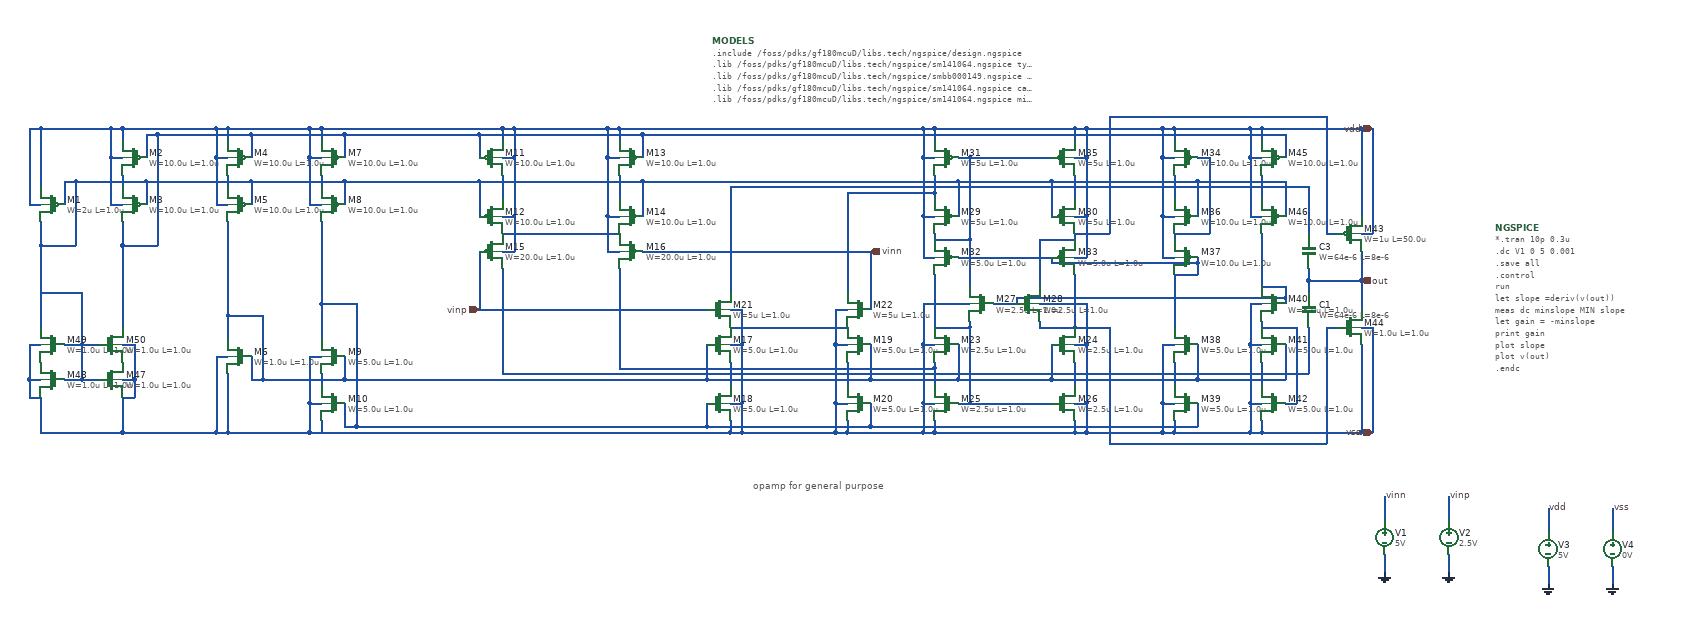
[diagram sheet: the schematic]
v {xschem version=3.4.8RC file_version=1.3}
G {}
K {}
V {}
S {}
F {}
E {}
P 4 1 -50 10 {}
T {opamp for general purpose} 600 240 2 0 0.4 0.4 {}
N 170 -150 190 -150 {
lab=vdd}
N 350 -150 370 -150 {
lab=vdd}
N 170 -360 170 -340 {
lab=vdd}
N 170 -310 190 -310 {
lab=vdd}
N 130 -350 130 -310 {
lab=#net1}
N 890 110 890 160 {
lab=vss}
N 890 110 910 110 {
lab=vss}
N 910 140 910 160 {
lab=vss}
N 910 -360 910 -340 {
lab=vdd}
N 890 -310 910 -310 {
lab=vdd}
N 1150 -360 1150 -340 {
lab=vdd}
N 1150 -310 1170 -310 {
lab=vdd}
N 1170 -310 1170 -210 {
lab=vdd}
N 1150 110 1170 110 {
lab=vss}
N 1150 140 1150 160 {
lab=vss}
N 130 -150 130 -50 {
lab=vinp}
N 740 -50 760 -50 {
lab=vss}
N 560 10 580 10 {
lab=vss}
N 580 110 580 160 {
lab=vss}
N 560 110 580 110 {
lab=vss}
N 560 40 560 80 {
lab=#net2}
N 560 140 560 160 {
lab=vss}
N 520 110 520 150 {
lab=#net3}
N 520 10 520 70 {
lab=#net4}
N 170 -210 190 -210 {
lab=vdd}
N 170 -280 170 -240 {
lab=#net5}
N 130 -270 130 -210 {
lab=#net6}
N 890 -310 890 -210 {
lab=vdd}
N 890 -210 910 -210 {
lab=vdd}
N 910 -250 910 -240 {
lab=#net7}
N 890 10 910 10 {
lab=vss}
N 890 10 890 110 {
lab=vss}
N 910 50 910 80 {
lab=#net8}
N 1150 60 1150 80 {
lab=#net9}
N 1150 10 1170 10 {
lab=vss}
N 410 -150 800 -150 {
lab=vinn}
N 800 -150 800 -50 {
lab=vinn}
N 1150 -210 1170 -210 {
lab=vdd}
N 1150 -260 1150 -240 {
lab=#net10}
N 170 -180 370 -180 {
lab=#net11}
N 130 -50 520 -50 {
lab=vinp}
N 560 -20 760 -20 {
lab=#net12}
N 910 -180 910 -170 {
lab=#net13}
N 890 -140 910 -140 {
lab=vdd}
N 890 -210 890 -140 {
lab=vdd}
N 970 110 1110 110 {
lab=#net14}
N 1170 110 1170 160 {
lab=vss}
N 1010 -60 1050 -60 {
lab=#net15}
N 1150 -140 1170 -140 {
lab=vdd}
N 1170 -210 1170 -140 {
lab=vdd}
N 1150 -180 1150 -170 {
lab=#net16}
N 1090 -60 1170 -60 {
lab=vss}
N 1170 -60 1170 10 {
lab=vss}
N 1640 -100 1640 -50 {
lab=out}
N 1640 -180 1660 -180 {
lab=vdd}
N 1660 -360 1660 -180 {
lab=vdd}
N 1320 -360 1450 -360 {
lab=vdd}
N 1640 -20 1660 -20 {
lab=vss}
N 1660 -20 1660 160 {
lab=vss}
N 1640 10 1640 160 {
lab=vss}
N 1640 -360 1640 -210 {
lab=vdd}
N 1300 -310 1320 -310 {
lab=vdd}
N 1300 -360 1300 -310 {
lab=vdd}
N 1320 -360 1320 -340 {
lab=vdd}
N 1320 -280 1320 -240 {
lab=#net17}
N 1300 -210 1320 -210 {
lab=vdd}
N 1300 -310 1300 -210 {
lab=vdd}
N 1320 -180 1320 -170 {
lab=#net18}
N 1300 -140 1320 -140 {
lab=vdd}
N 1300 -210 1300 -140 {
lab=vdd}
N 1300 10 1320 10 {
lab=vss}
N 1300 110 1300 160 {
lab=vss}
N 1300 110 1320 110 {
lab=vss}
N 1320 40 1320 80 {
lab=#net19}
N 1320 140 1320 160 {
lab=vss}
N 1360 110 1360 150 {
lab=#net3}
N 1360 10 1360 70 {
lab=#net4}
N 1450 -310 1470 -310 {
lab=vdd}
N 1450 -360 1450 -310 {
lab=vdd}
N 1470 -360 1470 -340 {
lab=vdd}
N 1470 -280 1470 -240 {
lab=#net20}
N 1450 -210 1470 -210 {
lab=vdd}
N 1450 -310 1450 -210 {
lab=vdd}
N 1450 10 1470 10 {
lab=vss}
N 1450 110 1450 160 {
lab=vss}
N 1450 110 1470 110 {
lab=vss}
N 1470 40 1470 80 {
lab=#net21}
N 1470 140 1470 160 {
lab=vss}
N 1470 -30 1470 -20 {
lab=#net22}
N 1450 -60 1470 -60 {
lab=vss}
N 1450 -60 1450 10 {
lab=vss}
N 1470 -360 1640 -360 {
lab=vdd}
N 370 -360 370 -340 {
lab=vdd}
N 350 -310 370 -310 {
lab=vdd}
N 410 -350 410 -310 {
lab=#net1}
N 350 -210 370 -210 {
lab=vdd}
N 370 -280 370 -240 {
lab=#net23}
N 410 -270 410 -210 {
lab=#net6}
N 740 10 760 10 {
lab=vss}
N 740 110 760 110 {
lab=vss}
N 760 40 760 80 {
lab=#net24}
N 760 140 760 160 {
lab=vss}
N 800 110 800 150 {
lab=#net3}
N 800 10 800 70 {
lab=#net4}
N 560 -50 580 -50 {
lab=vss}
N 1360 -270 1360 -210 {
lab=#net6}
N 1360 -310 1380 -310 {
lab=#net18}
N 1380 -310 1380 -180 {
lab=#net18}
N 1320 -180 1380 -180 {
lab=#net18}
N 1360 -130 1360 -110 {
lab=#net25}
N 1320 -110 1360 -110 {
lab=#net25}
N 1320 -110 1320 -20 {
lab=#net25}
N 1510 -350 1510 -310 {
lab=#net1}
N 1510 -270 1510 -210 {
lab=#net6}
N 1110 70 1360 70 {
lab=#net4}
N 1510 10 1510 70 {
lab=#net4}
N 1510 110 1530 110 {
lab=#net22}
N 1530 -20 1530 110 {
lab=#net22}
N 1470 -20 1530 -20 {
lab=#net22}
N 1510 -70 1510 -60 {
lab=#net15}
N 1470 -90 1510 -90 {
lab=#net15}
N 1470 -180 1470 -90 {
lab=#net15}
N 970 -310 1110 -310 {
lab=#net13}
N 950 -270 950 -210 {
lab=#net6}
N 1110 -270 1110 -210 {
lab=#net6}
N 950 -140 1110 -140 {
lab=#net25}
N 910 -110 910 -20 {
lab=#net14}
N 970 -30 970 -20 {
lab=#net14}
N 910 -20 970 -20 {
lab=#net14}
N 1090 -30 1090 -20 {
lab=#net26}
N 1090 -20 1150 -20 {
lab=#net26}
N 890 -60 970 -60 {
lab=vss}
N 890 -60 890 10 {
lab=vss}
N 1150 -110 1150 -20 {
lab=#net26}
N 970 -170 970 -90 {
lab=#net13}
N 910 -170 970 -170 {
lab=#net13}
N 1090 -170 1090 -90 {
lab=#net16}
N 1090 -170 1150 -170 {
lab=#net16}
N 1360 -270 1510 -270 {
lab=#net6}
N 800 150 1360 150 {
lab=#net3}
N 1360 70 1510 70 {
lab=#net4}
N 1110 -130 1360 -130 {
lab=#net25}
N 1110 -140 1110 -130 {
lab=#net25}
N 1050 -70 1510 -70 {
lab=#net15}
N 1050 -70 1050 -60 {
lab=#net15}
N 170 -120 170 60 {
lab=#net9}
N 370 -120 370 50 {
lab=#net8}
N 560 -260 560 -80 {
lab=#net10}
N 760 -250 760 -80 {
lab=#net7}
N 950 10 950 70 {
lab=#net4}
N 1110 10 1110 70 {
lab=#net4}
N 970 -20 970 110 {
lab=#net14}
N 970 -310 970 -170 {
lab=#net13}
N 1640 -360 1660 -360 {
lab=vdd}
N 1580 -180 1600 -180 {
lab=#net16}
N 1580 -380 1580 -180 {
lab=#net16}
N 1210 -380 1580 -380 {
lab=#net16}
N 1210 -380 1210 -180 {
lab=#net16}
N 1150 -180 1210 -180 {
lab=#net16}
N 1580 -20 1600 -20 {
lab=#net26}
N 1580 -20 1580 180 {
lab=#net26}
N 1210 180 1580 180 {
lab=#net26}
N 1210 -20 1210 180 {
lab=#net26}
N 1150 -20 1210 -20 {
lab=#net26}
N 1150 60 1550 60 {
lab=#net9}
N 1550 -100 1550 -80 {
lab=out}
N 560 -260 1150 -260 {
lab=#net10}
N 760 -250 910 -250 {
lab=#net7}
N 370 50 910 50 {
lab=#net8}
N 170 60 1150 60 {
lab=#net9}
N 890 -360 910 -360 {
lab=vdd}
N 1150 -360 1170 -360 {
lab=vdd}
N 1640 160 1660 160 {
lab=vss}
N 520 70 800 70 {
lab=#net4}
N 520 150 800 150 {
lab=#net3}
N 130 -350 410 -350 {
lab=#net1}
N 130 -270 410 -270 {
lab=#net6}
N 1110 -270 1360 -270 {
lab=#net6}
N 410 -350 1510 -350 {
lab=#net1}
N 350 -360 370 -360 {
lab=vdd}
N -20 -350 130 -350 {
lab=#net1}
N -20 -270 130 -270 {
lab=#net6}
N -20 70 520 70 {
lab=#net4}
N 0 150 520 150 {
lab=#net3}
N 1550 -100 1640 -100 {
lab=out}
N 1550 -20 1550 60 {
lab=#net9}
N 1150 -260 1550 -260 {
lab=#net10}
N 1550 -260 1550 -180 {
lab=#net10}
N 1550 -120 1550 -100 {
lab=out}
N 350 -310 350 -210 {
lab=vdd}
N 190 -310 190 -210 {
lab=vdd}
N 740 110 740 160 {
lab=vss}
N 580 -50 580 10 {
lab=vss}
N 740 -50 740 10 {
lab=vss}
N 190 -210 190 -150 {
lab=vdd}
N 350 -210 350 -150 {
lab=vdd}
N 190 -360 190 -310 {
lab=vdd}
N 760 160 890 160 {
lab=vss}
N 890 160 910 160 {
lab=vss}
N 890 -360 890 -310 {
lab=vdd}
N 910 -360 1150 -360 {
lab=vdd}
N 1170 -360 1170 -310 {
lab=vdd}
N 1170 10 1170 110 {
lab=vss}
N 910 160 1150 160 {
lab=vss}
N 560 160 580 160 {
lab=vss}
N 580 10 580 110 {
lab=vss}
N 1150 160 1170 160 {
lab=vss}
N 1470 160 1640 160 {
lab=vss}
N 1170 -360 1300 -360 {
lab=vdd}
N 1300 -360 1320 -360 {
lab=vdd}
N 1170 160 1300 160 {
lab=vss}
N 1300 10 1300 110 {
lab=vss}
N 1300 160 1320 160 {
lab=vss}
N 1450 -360 1470 -360 {
lab=vdd}
N 1320 160 1450 160 {
lab=vss}
N 1450 10 1450 110 {
lab=vss}
N 1450 160 1470 160 {
lab=vss}
N 350 -360 350 -310 {
lab=vdd}
N 740 10 740 110 {
lab=vss}
N 740 160 760 160 {
lab=vss}
N 410 -270 950 -270 {
lab=#net6}
N 950 -270 1110 -270 {
lab=#net6}
N 1360 -140 1360 -130 {
lab=#net25}
N 1510 -90 1510 -70 {
lab=#net15}
N 800 70 950 70 {
lab=#net4}
N 950 70 1110 70 {
lab=#net4}
N 950 110 970 110 {
lab=#net14}
N 950 -310 970 -310 {
lab=#net13}
N 1150 40 1150 60 {
lab=#net9}
N 1150 -280 1150 -260 {
lab=#net10}
N 910 -280 910 -250 {
lab=#net7}
N 910 40 910 50 {
lab=#net8}
N 1640 -150 1640 -100 {
lab=out}
N 580 160 740 160 {
lab=vss}
N 170 -360 190 -360 {
lab=vdd}
N 370 -360 890 -360 {
lab=vdd}
N 190 -360 350 -360 {
lab=vdd}
N -160 30 -140 30 {
lab=vss}
N -160 110 -160 160 {
lab=vss}
N -160 110 -140 110 {
lab=vss}
N -140 60 -140 80 {
lab=#net27}
N -140 140 -140 160 {
lab=vss}
N -140 -360 -140 -340 {
lab=vdd}
N -160 -310 -140 -310 {
lab=vdd}
N -160 -230 -140 -230 {
lab=vdd}
N -160 -310 -160 -230 {
lab=vdd}
N -140 -280 -140 -260 {
lab=#net28}
N -100 -270 -100 -230 {
lab=#net6}
N -100 -350 -100 -310 {
lab=#net1}
N -300 -360 -300 -340 {
lab=vdd}
N -320 -310 -300 -310 {
lab=vdd}
N -320 -230 -300 -230 {
lab=vdd}
N -320 -310 -320 -230 {
lab=vdd}
N -300 -280 -300 -260 {
lab=#net29}
N -260 -270 -260 -230 {
lab=#net6}
N -260 -350 -260 -310 {
lab=#net1}
N -320 30 -300 30 {
lab=vss}
N -320 30 -320 160 {
lab=vss}
N -300 60 -300 160 {
lab=vss}
N -260 30 -260 70 {
lab=#net4}
N -260 70 -240 70 {
lab=#net4}
N -300 -40 -240 -40 {
lab=#net4}
N -100 30 -100 70 {
lab=#net4}
N -100 110 -100 150 {
lab=#net3}
N -100 150 -80 150 {
lab=#net3}
N -240 70 -100 70 {
lab=#net4}
N -140 -60 -80 -60 {
lab=#net3}
N -300 -200 -300 -40 {
lab=#net4}
N -140 -200 -140 -60 {
lab=#net3}
N -240 -40 -240 70 {
lab=#net4}
N -80 -60 -80 150 {
lab=#net3}
N -140 -60 -140 0 {
lab=#net3}
N -300 -40 -300 0 {
lab=#net4}
N -100 -350 50 -350 {
lab=#net1}
N -100 -270 50 -270 {
lab=#net6}
N -480 160 -320 160 {
lab=vss}
N -480 -360 -480 -340 {
lab=vdd}
N -500 -310 -480 -310 {
lab=vdd}
N -500 -230 -480 -230 {
lab=vdd}
N -500 -310 -500 -230 {
lab=vdd}
N -480 -280 -480 -260 {
lab=#net30}
N -440 -270 -440 -230 {
lab=#net6}
N -440 -350 -440 -310 {
lab=#net1}
N -480 -160 -420 -160 {
lab=#net1}
N -480 -160 -480 -20 {
lab=#net1}
N -620 -360 -620 -260 {
lab=vdd}
N -640 -230 -620 -230 {
lab=vdd}
N -640 -360 -640 -230 {
lab=vdd}
N -560 -270 -440 -270 {
lab=#net6}
N -580 -270 -580 -230 {
lab=#net6}
N -620 -160 -560 -160 {
lab=#net6}
N -620 -160 -620 -20 {
lab=#net6}
N -620 -200 -620 -160 {
lab=#net6}
N -480 -200 -480 -160 {
lab=#net1}
N -560 -270 -560 -160 {
lab=#net6}
N -420 -350 -420 -160 {
lab=#net1}
N -620 100 -620 160 {
lab=vss}
N -480 100 -480 160 {
lab=vss}
N -550 70 -520 70 {
lab=#net6}
N -640 70 -620 70 {
lab=vss}
N -640 70 -640 100 {
lab=vss}
N -640 100 -620 100 {
lab=vss}
N -480 70 -460 70 {
lab=vss}
N -460 70 -460 100 {
lab=vss}
N -480 100 -460 100 {
lab=vss}
N -550 10 -520 10 {
lab=#net6}
N -550 10 -550 70 {
lab=#net6}
N -640 10 -620 10 {
lab=vss}
N -640 10 -640 70 {
lab=vss}
N -480 10 -460 10 {
lab=vss}
N -460 10 -460 70 {
lab=vss}
N -550 -10 -550 10 {
lab=#net6}
N -300 160 -160 160 {
lab=vss}
N -160 30 -160 110 {
lab=vss}
N -160 160 -140 160 {
lab=vss}
N -160 -360 -140 -360 {
lab=vdd}
N -160 -360 -160 -310 {
lab=vdd}
N -260 -270 -100 -270 {
lab=#net6}
N -260 -350 -100 -350 {
lab=#net1}
N -320 -360 -300 -360 {
lab=vdd}
N -320 -360 -320 -310 {
lab=vdd}
N -440 -270 -260 -270 {
lab=#net6}
N -420 -350 -260 -350 {
lab=#net1}
N -320 160 -300 160 {
lab=vss}
N -500 -360 -480 -360 {
lab=vdd}
N -500 -360 -500 -310 {
lab=vdd}
N -640 -360 -620 -360 {
lab=vdd}
N -580 -270 -560 -270 {
lab=#net6}
N -440 -350 -420 -350 {
lab=#net1}
N -620 160 -480 160 {
lab=vss}
N -580 10 -550 10 {
lab=#net6}
N -580 70 -550 70 {
lab=#net6}
N -300 -360 -160 -360 {
lab=vdd}
N -480 -360 -320 -360 {
lab=vdd}
N -620 -360 -500 -360 {
lab=vdd}
N -620 -80 -550 -80 {lab=#net6}
N -550 -80 -550 -10 {lab=#net6}
N -100 70 40 70 {lab=#net4}
N -80 150 40 150 {lab=#net3}
N -140 -360 170 -360 {lab=vdd}
N -150 160 560 160 {lab=vss}
N 1680 370 1680 400 {lab=GND}
N 1680 270 1680 310 {lab=vinn}
N 1790 370 1790 400 {lab=GND}
N 1790 270 1790 310 {lab=vinp}
N 1960 390 1960 420 {lab=GND}
N 1960 290 1960 330 {lab=vdd}
N 2070 390 2070 420 {lab=GND}
N 2070 290 2070 330 {lab=vss}
C {devices/opin.sym} 1640 -100 0 0 {name=p1 lab=out}
C {devices/iopin.sym} 1660 -360 0 0 {name=p3 lab=vdd}
C {devices/iopin.sym} 1660 160 0 0 {name=p4 lab=vss}
C {devices/ipin.sym} 130 -50 0 0 {name=p2 lab=vinp}
C {devices/ipin.sym} 800 -150 0 1 {name=p5 lab=vinn}
C {symbols/pfet_06v0.sym} 150 -310 0 0 {name=M11
L=1.0u
W=10.0u
nf=1
m=1
ad="'int((nf+1)/2) * W/nf * 0.18u'"
pd="'2*int((nf+1)/2) * (W/nf + 0.18u)'"
as="'int((nf+2)/2) * W/nf * 0.18u'"
ps="'2*int((nf+2)/2) * (W/nf + 0.18u)'"
nrd="'0.18u / W'" nrs="'0.18u / W'"
sa=0 sb=0 sd=0
model=pfet_06v0
spiceprefix=X
}
C {symbols/pfet_06v0.sym} 150 -210 0 0 {name=M12
L=1.0u
W=10.0u
nf=1
m=1
ad="'int((nf+1)/2) * W/nf * 0.18u'"
pd="'2*int((nf+1)/2) * (W/nf + 0.18u)'"
as="'int((nf+2)/2) * W/nf * 0.18u'"
ps="'2*int((nf+2)/2) * (W/nf + 0.18u)'"
nrd="'0.18u / W'" nrs="'0.18u / W'"
sa=0 sb=0 sd=0
model=pfet_06v0
spiceprefix=X
}
C {symbols/pfet_06v0.sym} 390 -310 0 1 {name=M13
L=1.0u
W=10.0u
nf=1
m=1
ad="'int((nf+1)/2) * W/nf * 0.18u'"
pd="'2*int((nf+1)/2) * (W/nf + 0.18u)'"
as="'int((nf+2)/2) * W/nf * 0.18u'"
ps="'2*int((nf+2)/2) * (W/nf + 0.18u)'"
nrd="'0.18u / W'" nrs="'0.18u / W'"
sa=0 sb=0 sd=0
model=pfet_06v0
spiceprefix=X
}
C {symbols/pfet_06v0.sym} 390 -210 0 1 {name=M14
L=1.0u
W=10.0u
nf=1
m=1
ad="'int((nf+1)/2) * W/nf * 0.18u'"
pd="'2*int((nf+1)/2) * (W/nf + 0.18u)'"
as="'int((nf+2)/2) * W/nf * 0.18u'"
ps="'2*int((nf+2)/2) * (W/nf + 0.18u)'"
nrd="'0.18u / W'" nrs="'0.18u / W'"
sa=0 sb=0 sd=0
model=pfet_06v0
spiceprefix=X
}
C {symbols/pfet_06v0.sym} 150 -150 0 0 {name=M15
L=1.0u
W=20.0u
nf=2
m=1
ad="'int((nf+1)/2) * W/nf * 0.18u'"
pd="'2*int((nf+1)/2) * (W/nf + 0.18u)'"
as="'int((nf+2)/2) * W/nf * 0.18u'"
ps="'2*int((nf+2)/2) * (W/nf + 0.18u)'"
nrd="'0.18u / W'" nrs="'0.18u / W'"
sa=0 sb=0 sd=0
model=pfet_06v0
spiceprefix=X
}
C {symbols/pfet_06v0.sym} 390 -150 0 1 {name=M16
L=1.0u
W=20.0u
nf=2
m=1
ad="'int((nf+1)/2) * W/nf * 0.18u'"
pd="'2*int((nf+1)/2) * (W/nf + 0.18u)'"
as="'int((nf+2)/2) * W/nf * 0.18u'"
ps="'2*int((nf+2)/2) * (W/nf + 0.18u)'"
nrd="'0.18u / W'" nrs="'0.18u / W'"
sa=0 sb=0 sd=0
model=pfet_06v0
spiceprefix=X
}
C {symbols/nfet_06v0.sym} 540 10 0 0 {name=M17
L=1.0u
W=5.0u
nf=1
m=1
ad="'int((nf+1)/2) * W/nf * 0.18u'"
pd="'2*int((nf+1)/2) * (W/nf + 0.18u)'"
as="'int((nf+2)/2) * W/nf * 0.18u'"
ps="'2*int((nf+2)/2) * (W/nf + 0.18u)'"
nrd="'0.18u / W'" nrs="'0.18u / W'"
sa=0 sb=0 sd=0
model=nfet_06v0
spiceprefix=X
}
C {symbols/nfet_06v0.sym} 540 110 0 0 {name=M18
L=1.0u
W=5.0u
nf=1
m=1
ad="'int((nf+1)/2) * W/nf * 0.18u'"
pd="'2*int((nf+1)/2) * (W/nf + 0.18u)'"
as="'int((nf+2)/2) * W/nf * 0.18u'"
ps="'2*int((nf+2)/2) * (W/nf + 0.18u)'"
nrd="'0.18u / W'" nrs="'0.18u / W'"
sa=0 sb=0 sd=0
model=nfet_06v0
spiceprefix=X
}
C {symbols/nfet_06v0.sym} 780 10 0 1 {name=M19
L=1.0u
W=5.0u
nf=1
m=1
ad="'int((nf+1)/2) * W/nf * 0.18u'"
pd="'2*int((nf+1)/2) * (W/nf + 0.18u)'"
as="'int((nf+2)/2) * W/nf * 0.18u'"
ps="'2*int((nf+2)/2) * (W/nf + 0.18u)'"
nrd="'0.18u / W'" nrs="'0.18u / W'"
sa=0 sb=0 sd=0
model=nfet_06v0
spiceprefix=X
}
C {symbols/nfet_06v0.sym} 780 110 0 1 {name=M20
L=1.0u
W=5.0u
nf=1
m=1
ad="'int((nf+1)/2) * W/nf * 0.18u'"
pd="'2*int((nf+1)/2) * (W/nf + 0.18u)'"
as="'int((nf+2)/2) * W/nf * 0.18u'"
ps="'2*int((nf+2)/2) * (W/nf + 0.18u)'"
nrd="'0.18u / W'" nrs="'0.18u / W'"
sa=0 sb=0 sd=0
model=nfet_06v0
spiceprefix=X
}
C {symbols/nfet_06v0.sym} 540 -50 0 0 {name=M21
L=1.0u
W=5u
nf=2
m=1
ad="'int((nf+1)/2) * W/nf * 0.18u'"
pd="'2*int((nf+1)/2) * (W/nf + 0.18u)'"
as="'int((nf+2)/2) * W/nf * 0.18u'"
ps="'2*int((nf+2)/2) * (W/nf + 0.18u)'"
nrd="'0.18u / W'" nrs="'0.18u / W'"
sa=0 sb=0 sd=0
model=nfet_06v0
spiceprefix=X
}
C {symbols/nfet_06v0.sym} 780 -50 0 1 {name=M22
L=1.0u
W=5u
nf=2
m=1
ad="'int((nf+1)/2) * W/nf * 0.18u'"
pd="'2*int((nf+1)/2) * (W/nf + 0.18u)'"
as="'int((nf+2)/2) * W/nf * 0.18u'"
ps="'2*int((nf+2)/2) * (W/nf + 0.18u)'"
nrd="'0.18u / W'" nrs="'0.18u / W'"
sa=0 sb=0 sd=0
model=nfet_06v0
spiceprefix=X
}
C {symbols/pfet_06v0.sym} 930 -210 0 1 {name=M29
L=1.0u
W=5u
nf=2
m=1
ad="'int((nf+1)/2) * W/nf * 0.18u'"
pd="'2*int((nf+1)/2) * (W/nf + 0.18u)'"
as="'int((nf+2)/2) * W/nf * 0.18u'"
ps="'2*int((nf+2)/2) * (W/nf + 0.18u)'"
nrd="'0.18u / W'" nrs="'0.18u / W'"
sa=0 sb=0 sd=0
model=pfet_06v0
spiceprefix=X
}
C {symbols/pfet_06v0.sym} 1130 -210 0 0 {name=M30
L=1.0u
W=5u
nf=2
m=1
ad="'int((nf+1)/2) * W/nf * 0.18u'"
pd="'2*int((nf+1)/2) * (W/nf + 0.18u)'"
as="'int((nf+2)/2) * W/nf * 0.18u'"
ps="'2*int((nf+2)/2) * (W/nf + 0.18u)'"
nrd="'0.18u / W'" nrs="'0.18u / W'"
sa=0 sb=0 sd=0
model=pfet_06v0
spiceprefix=X
}
C {symbols/pfet_06v0.sym} 930 -310 0 1 {name=M31
L=1.0u
W=5u
nf=4
m=1
ad="'int((nf+1)/2) * W/nf * 0.18u'"
pd="'2*int((nf+1)/2) * (W/nf + 0.18u)'"
as="'int((nf+2)/2) * W/nf * 0.18u'"
ps="'2*int((nf+2)/2) * (W/nf + 0.18u)'"
nrd="'0.18u / W'" nrs="'0.18u / W'"
sa=0 sb=0 sd=0
model=pfet_06v0
spiceprefix=X
}
C {symbols/pfet_06v0.sym} 1130 -310 0 0 {name=M35
L=1.0u
W=5u
nf=4
m=1
ad="'int((nf+1)/2) * W/nf * 0.18u'"
pd="'2*int((nf+1)/2) * (W/nf + 0.18u)'"
as="'int((nf+2)/2) * W/nf * 0.18u'"
ps="'2*int((nf+2)/2) * (W/nf + 0.18u)'"
nrd="'0.18u / W'" nrs="'0.18u / W'"
sa=0 sb=0 sd=0
model=pfet_06v0
spiceprefix=X
}
C {symbols/pfet_06v0.sym} 930 -140 0 1 {name=M32
L=1.0u
W=5.0u
nf=2
m=1
ad="'int((nf+1)/2) * W/nf * 0.18u'"
pd="'2*int((nf+1)/2) * (W/nf + 0.18u)'"
as="'int((nf+2)/2) * W/nf * 0.18u'"
ps="'2*int((nf+2)/2) * (W/nf + 0.18u)'"
nrd="'0.18u / W'" nrs="'0.18u / W'"
sa=0 sb=0 sd=0
model=pfet_06v0
spiceprefix=X
}
C {symbols/pfet_06v0.sym} 1130 -140 0 0 {name=M33
L=1.0u
W=5.0u
nf=2
m=1
ad="'int((nf+1)/2) * W/nf * 0.18u'"
pd="'2*int((nf+1)/2) * (W/nf + 0.18u)'"
as="'int((nf+2)/2) * W/nf * 0.18u'"
ps="'2*int((nf+2)/2) * (W/nf + 0.18u)'"
nrd="'0.18u / W'" nrs="'0.18u / W'"
sa=0 sb=0 sd=0
model=pfet_06v0
spiceprefix=X
}
C {symbols/nfet_06v0.sym} 930 10 0 1 {name=M23
L=1.0u
W=2.5u
nf=2
m=1
ad="'int((nf+1)/2) * W/nf * 0.18u'"
pd="'2*int((nf+1)/2) * (W/nf + 0.18u)'"
as="'int((nf+2)/2) * W/nf * 0.18u'"
ps="'2*int((nf+2)/2) * (W/nf + 0.18u)'"
nrd="'0.18u / W'" nrs="'0.18u / W'"
sa=0 sb=0 sd=0
model=nfet_06v0
spiceprefix=X
}
C {symbols/nfet_06v0.sym} 1130 10 0 0 {name=M24
L=1.0u
W=2.5u
nf=2
m=1
ad="'int((nf+1)/2) * W/nf * 0.18u'"
pd="'2*int((nf+1)/2) * (W/nf + 0.18u)'"
as="'int((nf+2)/2) * W/nf * 0.18u'"
ps="'2*int((nf+2)/2) * (W/nf + 0.18u)'"
nrd="'0.18u / W'" nrs="'0.18u / W'"
sa=0 sb=0 sd=0
model=nfet_06v0
spiceprefix=X
}
C {symbols/nfet_06v0.sym} 930 110 0 1 {name=M25
L=1.0u
W=2.5u
nf=4
m=1
ad="'int((nf+1)/2) * W/nf * 0.18u'"
pd="'2*int((nf+1)/2) * (W/nf + 0.18u)'"
as="'int((nf+2)/2) * W/nf * 0.18u'"
ps="'2*int((nf+2)/2) * (W/nf + 0.18u)'"
nrd="'0.18u / W'" nrs="'0.18u / W'"
sa=0 sb=0 sd=0
model=nfet_06v0
spiceprefix=X
}
C {symbols/nfet_06v0.sym} 1130 110 0 0 {name=M26
L=1.0u
W=2.5u
nf=4
m=1
ad="'int((nf+1)/2) * W/nf * 0.18u'"
pd="'2*int((nf+1)/2) * (W/nf + 0.18u)'"
as="'int((nf+2)/2) * W/nf * 0.18u'"
ps="'2*int((nf+2)/2) * (W/nf + 0.18u)'"
nrd="'0.18u / W'" nrs="'0.18u / W'"
sa=0 sb=0 sd=0
model=nfet_06v0
spiceprefix=X
}
C {symbols/nfet_06v0.sym} 990 -60 0 1 {name=M27
L=1.0u
W=2.5u
nf=1
m=1
ad="'int((nf+1)/2) * W/nf * 0.18u'"
pd="'2*int((nf+1)/2) * (W/nf + 0.18u)'"
as="'int((nf+2)/2) * W/nf * 0.18u'"
ps="'2*int((nf+2)/2) * (W/nf + 0.18u)'"
nrd="'0.18u / W'" nrs="'0.18u / W'"
sa=0 sb=0 sd=0
model=nfet_06v0
spiceprefix=X
}
C {symbols/nfet_06v0.sym} 1070 -60 0 0 {name=M28
L=1.0u
W=2.5u
nf=1
m=1
ad="'int((nf+1)/2) * W/nf * 0.18u'"
pd="'2*int((nf+1)/2) * (W/nf + 0.18u)'"
as="'int((nf+2)/2) * W/nf * 0.18u'"
ps="'2*int((nf+2)/2) * (W/nf + 0.18u)'"
nrd="'0.18u / W'" nrs="'0.18u / W'"
sa=0 sb=0 sd=0
model=nfet_06v0
spiceprefix=X
}
C {symbols/pfet_06v0.sym} 1340 -310 0 1 {name=M34
L=1.0u
W=10.0u
nf=1
m=1
ad="'int((nf+1)/2) * W/nf * 0.18u'"
pd="'2*int((nf+1)/2) * (W/nf + 0.18u)'"
as="'int((nf+2)/2) * W/nf * 0.18u'"
ps="'2*int((nf+2)/2) * (W/nf + 0.18u)'"
nrd="'0.18u / W'" nrs="'0.18u / W'"
sa=0 sb=0 sd=0
model=pfet_06v0
spiceprefix=X
}
C {symbols/pfet_06v0.sym} 1340 -210 0 1 {name=M36
L=1.0u
W=10.0u
nf=1
m=1
ad="'int((nf+1)/2) * W/nf * 0.18u'"
pd="'2*int((nf+1)/2) * (W/nf + 0.18u)'"
as="'int((nf+2)/2) * W/nf * 0.18u'"
ps="'2*int((nf+2)/2) * (W/nf + 0.18u)'"
nrd="'0.18u / W'" nrs="'0.18u / W'"
sa=0 sb=0 sd=0
model=pfet_06v0
spiceprefix=X
}
C {symbols/pfet_06v0.sym} 1340 -140 0 1 {name=M37
L=1.0u
W=10.0u
nf=1
m=1
ad="'int((nf+1)/2) * W/nf * 0.18u'"
pd="'2*int((nf+1)/2) * (W/nf + 0.18u)'"
as="'int((nf+2)/2) * W/nf * 0.18u'"
ps="'2*int((nf+2)/2) * (W/nf + 0.18u)'"
nrd="'0.18u / W'" nrs="'0.18u / W'"
sa=0 sb=0 sd=0
model=pfet_06v0
spiceprefix=X
}
C {symbols/nfet_06v0.sym} 1340 10 0 1 {name=M38
L=1.0u
W=5.0u
nf=1
m=1
ad="'int((nf+1)/2) * W/nf * 0.18u'"
pd="'2*int((nf+1)/2) * (W/nf + 0.18u)'"
as="'int((nf+2)/2) * W/nf * 0.18u'"
ps="'2*int((nf+2)/2) * (W/nf + 0.18u)'"
nrd="'0.18u / W'" nrs="'0.18u / W'"
sa=0 sb=0 sd=0
model=nfet_06v0
spiceprefix=X
}
C {symbols/nfet_06v0.sym} 1340 110 0 1 {name=M39
L=1.0u
W=5.0u
nf=1
m=1
ad="'int((nf+1)/2) * W/nf * 0.18u'"
pd="'2*int((nf+1)/2) * (W/nf + 0.18u)'"
as="'int((nf+2)/2) * W/nf * 0.18u'"
ps="'2*int((nf+2)/2) * (W/nf + 0.18u)'"
nrd="'0.18u / W'" nrs="'0.18u / W'"
sa=0 sb=0 sd=0
model=nfet_06v0
spiceprefix=X
}
C {symbols/pfet_06v0.sym} 1490 -310 0 1 {name=M45
L=1.0u
W=10.0u
nf=1
m=1
ad="'int((nf+1)/2) * W/nf * 0.18u'"
pd="'2*int((nf+1)/2) * (W/nf + 0.18u)'"
as="'int((nf+2)/2) * W/nf * 0.18u'"
ps="'2*int((nf+2)/2) * (W/nf + 0.18u)'"
nrd="'0.18u / W'" nrs="'0.18u / W'"
sa=0 sb=0 sd=0
model=pfet_06v0
spiceprefix=X
}
C {symbols/pfet_06v0.sym} 1490 -210 0 1 {name=M46
L=1.0u
W=10.0u
nf=1
m=1
ad="'int((nf+1)/2) * W/nf * 0.18u'"
pd="'2*int((nf+1)/2) * (W/nf + 0.18u)'"
as="'int((nf+2)/2) * W/nf * 0.18u'"
ps="'2*int((nf+2)/2) * (W/nf + 0.18u)'"
nrd="'0.18u / W'" nrs="'0.18u / W'"
sa=0 sb=0 sd=0
model=pfet_06v0
spiceprefix=X
}
C {symbols/nfet_06v0.sym} 1490 -60 0 1 {name=M40
L=1.0u
W=5.0u
nf=1
m=1
ad="'int((nf+1)/2) * W/nf * 0.18u'"
pd="'2*int((nf+1)/2) * (W/nf + 0.18u)'"
as="'int((nf+2)/2) * W/nf * 0.18u'"
ps="'2*int((nf+2)/2) * (W/nf + 0.18u)'"
nrd="'0.18u / W'" nrs="'0.18u / W'"
sa=0 sb=0 sd=0
model=nfet_06v0
spiceprefix=X
}
C {symbols/nfet_06v0.sym} 1490 10 0 1 {name=M41
L=1.0u
W=5.0u
nf=1
m=1
ad="'int((nf+1)/2) * W/nf * 0.18u'"
pd="'2*int((nf+1)/2) * (W/nf + 0.18u)'"
as="'int((nf+2)/2) * W/nf * 0.18u'"
ps="'2*int((nf+2)/2) * (W/nf + 0.18u)'"
nrd="'0.18u / W'" nrs="'0.18u / W'"
sa=0 sb=0 sd=0
model=nfet_06v0
spiceprefix=X
}
C {symbols/nfet_06v0.sym} 1490 110 0 1 {name=M42
L=1.0u
W=5.0u
nf=1
m=1
ad="'int((nf+1)/2) * W/nf * 0.18u'"
pd="'2*int((nf+1)/2) * (W/nf + 0.18u)'"
as="'int((nf+2)/2) * W/nf * 0.18u'"
ps="'2*int((nf+2)/2) * (W/nf + 0.18u)'"
nrd="'0.18u / W'" nrs="'0.18u / W'"
sa=0 sb=0 sd=0
model=nfet_06v0
spiceprefix=X
}
C {symbols/pfet_06v0.sym} 1620 -180 0 0 {name=M43
L=50.0u
W=1u
nf=1
m=1
ad="'int((nf+1)/2) * W/nf * 0.18u'"
pd="'2*int((nf+1)/2) * (W/nf + 0.18u)'"
as="'int((nf+2)/2) * W/nf * 0.18u'"
ps="'2*int((nf+2)/2) * (W/nf + 0.18u)'"
nrd="'0.18u / W'" nrs="'0.18u / W'"
sa=0 sb=0 sd=0
model=pfet_06v0
spiceprefix=X
}
C {symbols/nfet_06v0.sym} 1620 -20 0 0 {name=M44
L=1.0u
W=1.0u
nf=14
m=1
ad="'int((nf+1)/2) * W/nf * 0.18u'"
pd="'2*int((nf+1)/2) * (W/nf + 0.18u)'"
as="'int((nf+2)/2) * W/nf * 0.18u'"
ps="'2*int((nf+2)/2) * (W/nf + 0.18u)'"
nrd="'0.18u / W'" nrs="'0.18u / W'"
sa=0 sb=0 sd=0
model=nfet_06v0
spiceprefix=X
}
C {symbols/cap_mim_2f0fF.sym} 1550 -150 0 0 {name=C3
W=64e-6
L=8e-6
model=cap_mim_2f0fF
spiceprefix=X
m=1}
C {symbols/cap_mim_2f0fF.sym} 1550 -50 0 0 {name=C1
W=64e-6
L=8e-6
model=cap_mim_2f0fF
spiceprefix=X
m=1}
C {symbols/pfet_06v0.sym} -280 -310 0 1 {name=M4
L=1.0u
W=10.0u
nf=1
m=1
ad="'int((nf+1)/2) * W/nf * 0.18u'"
pd="'2*int((nf+1)/2) * (W/nf + 0.18u)'"
as="'int((nf+2)/2) * W/nf * 0.18u'"
ps="'2*int((nf+2)/2) * (W/nf + 0.18u)'"
nrd="'0.18u / W'" nrs="'0.18u / W'"
sa=0 sb=0 sd=0
model=pfet_06v0
spiceprefix=X
}
C {symbols/pfet_06v0.sym} -280 -230 0 1 {name=M5
L=1.0u
W=10.0u
nf=1
m=1
ad="'int((nf+1)/2) * W/nf * 0.18u'"
pd="'2*int((nf+1)/2) * (W/nf + 0.18u)'"
as="'int((nf+2)/2) * W/nf * 0.18u'"
ps="'2*int((nf+2)/2) * (W/nf + 0.18u)'"
nrd="'0.18u / W'" nrs="'0.18u / W'"
sa=0 sb=0 sd=0
model=pfet_06v0
spiceprefix=X
}
C {symbols/nfet_06v0.sym} -280 30 0 1 {name=M6
L=1.0u
W=1.0u
nf=1
m=1
ad="'int((nf+1)/2) * W/nf * 0.18u'"
pd="'2*int((nf+1)/2) * (W/nf + 0.18u)'"
as="'int((nf+2)/2) * W/nf * 0.18u'"
ps="'2*int((nf+2)/2) * (W/nf + 0.18u)'"
nrd="'0.18u / W'" nrs="'0.18u / W'"
sa=0 sb=0 sd=0
model=nfet_06v0
spiceprefix=X
}
C {symbols/pfet_06v0.sym} -120 -310 0 1 {name=M7
L=1.0u
W=10.0u
nf=1
m=1
ad="'int((nf+1)/2) * W/nf * 0.18u'"
pd="'2*int((nf+1)/2) * (W/nf + 0.18u)'"
as="'int((nf+2)/2) * W/nf * 0.18u'"
ps="'2*int((nf+2)/2) * (W/nf + 0.18u)'"
nrd="'0.18u / W'" nrs="'0.18u / W'"
sa=0 sb=0 sd=0
model=pfet_06v0
spiceprefix=X
}
C {symbols/pfet_06v0.sym} -120 -230 0 1 {name=M8
L=1.0u
W=10.0u
nf=1
m=1
ad="'int((nf+1)/2) * W/nf * 0.18u'"
pd="'2*int((nf+1)/2) * (W/nf + 0.18u)'"
as="'int((nf+2)/2) * W/nf * 0.18u'"
ps="'2*int((nf+2)/2) * (W/nf + 0.18u)'"
nrd="'0.18u / W'" nrs="'0.18u / W'"
sa=0 sb=0 sd=0
model=pfet_06v0
spiceprefix=X
}
C {symbols/nfet_06v0.sym} -120 30 0 1 {name=M9
L=1.0u
W=5.0u
nf=1
m=1
ad="'int((nf+1)/2) * W/nf * 0.18u'"
pd="'2*int((nf+1)/2) * (W/nf + 0.18u)'"
as="'int((nf+2)/2) * W/nf * 0.18u'"
ps="'2*int((nf+2)/2) * (W/nf + 0.18u)'"
nrd="'0.18u / W'" nrs="'0.18u / W'"
sa=0 sb=0 sd=0
model=nfet_06v0
spiceprefix=X
}
C {symbols/nfet_06v0.sym} -120 110 0 1 {name=M10
L=1.0u
W=5.0u
nf=1
m=1
ad="'int((nf+1)/2) * W/nf * 0.18u'"
pd="'2*int((nf+1)/2) * (W/nf + 0.18u)'"
as="'int((nf+2)/2) * W/nf * 0.18u'"
ps="'2*int((nf+2)/2) * (W/nf + 0.18u)'"
nrd="'0.18u / W'" nrs="'0.18u / W'"
sa=0 sb=0 sd=0
model=nfet_06v0
spiceprefix=X
}
C {symbols/pfet_06v0.sym} -600 -230 0 1 {name=M1
L=1.0u
W=2u
nf=1
m=1
ad="'int((nf+1)/2) * W/nf * 0.18u'"
pd="'2*int((nf+1)/2) * (W/nf + 0.18u)'"
as="'int((nf+2)/2) * W/nf * 0.18u'"
ps="'2*int((nf+2)/2) * (W/nf + 0.18u)'"
nrd="'0.18u / W'" nrs="'0.18u / W'"
sa=0 sb=0 sd=0
model=pfet_06v0
spiceprefix=X
}
C {symbols/pfet_06v0.sym} -460 -310 0 1 {name=M2
L=1.0u
W=10.0u
nf=1
m=1
ad="'int((nf+1)/2) * W/nf * 0.18u'"
pd="'2*int((nf+1)/2) * (W/nf + 0.18u)'"
as="'int((nf+2)/2) * W/nf * 0.18u'"
ps="'2*int((nf+2)/2) * (W/nf + 0.18u)'"
nrd="'0.18u / W'" nrs="'0.18u / W'"
sa=0 sb=0 sd=0
model=pfet_06v0
spiceprefix=X
}
C {symbols/pfet_06v0.sym} -460 -230 0 1 {name=M3
L=1.0u
W=10.0u
nf=1
m=1
ad="'int((nf+1)/2) * W/nf * 0.18u'"
pd="'2*int((nf+1)/2) * (W/nf + 0.18u)'"
as="'int((nf+2)/2) * W/nf * 0.18u'"
ps="'2*int((nf+2)/2) * (W/nf + 0.18u)'"
nrd="'0.18u / W'" nrs="'0.18u / W'"
sa=0 sb=0 sd=0
model=pfet_06v0
spiceprefix=X
}
C {symbols/nfet_06v0.sym} -500 70 0 0 {name=M47
L=1.0u
W=1.0u
nf=1
m=1
ad="'int((nf+1)/2) * W/nf * 0.18u'"
pd="'2*int((nf+1)/2) * (W/nf + 0.18u)'"
as="'int((nf+2)/2) * W/nf * 0.18u'"
ps="'2*int((nf+2)/2) * (W/nf + 0.18u)'"
nrd="'0.18u / W'" nrs="'0.18u / W'"
sa=0 sb=0 sd=0
model=nfet_06v0
spiceprefix=X
}
C {symbols/nfet_06v0.sym} -600 70 0 1 {name=M48
L=1.0u
W=1.0u
nf=1
m=1
ad="'int((nf+1)/2) * W/nf * 0.18u'"
pd="'2*int((nf+1)/2) * (W/nf + 0.18u)'"
as="'int((nf+2)/2) * W/nf * 0.18u'"
ps="'2*int((nf+2)/2) * (W/nf + 0.18u)'"
nrd="'0.18u / W'" nrs="'0.18u / W'"
sa=0 sb=0 sd=0
model=nfet_06v0
spiceprefix=X
}
C {symbols/nfet_06v0.sym} -600 10 0 1 {name=M49
L=1.0u
W=1.0u
nf=1
m=1
ad="'int((nf+1)/2) * W/nf * 0.18u'"
pd="'2*int((nf+1)/2) * (W/nf + 0.18u)'"
as="'int((nf+2)/2) * W/nf * 0.18u'"
ps="'2*int((nf+2)/2) * (W/nf + 0.18u)'"
nrd="'0.18u / W'" nrs="'0.18u / W'"
sa=0 sb=0 sd=0
model=nfet_06v0
spiceprefix=X
}
C {symbols/nfet_06v0.sym} -500 10 0 0 {name=M50
L=1.0u
W=1.0u
nf=1
m=1
ad="'int((nf+1)/2) * W/nf * 0.18u'"
pd="'2*int((nf+1)/2) * (W/nf + 0.18u)'"
as="'int((nf+2)/2) * W/nf * 0.18u'"
ps="'2*int((nf+2)/2) * (W/nf + 0.18u)'"
nrd="'0.18u / W'" nrs="'0.18u / W'"
sa=0 sb=0 sd=0
model=nfet_06v0
spiceprefix=X
}
C {vsource.sym} 1680 340 0 0 {name=V1 value=5V savecurrent=false}
C {gnd.sym} 1680 400 0 0 {name=l6 lab=GND}
C {vsource.sym} 1790 340 0 0 {name=V2 value=2.5V savecurrent=false}
C {gnd.sym} 1790 400 0 0 {name=l5 lab=GND}
C {lab_pin.sym} 1790 270 2 0 {name=p11 sig_type=std_logic lab=vinp}
C {lab_pin.sym} 1680 270 2 0 {name=p6 sig_type=std_logic lab=vinn
}
C {vsource.sym} 1960 360 0 0 {name=V3 value=5V savecurrent=false}
C {gnd.sym} 1960 420 0 0 {name=l1 lab=GND}
C {lab_pin.sym} 1960 290 2 0 {name=p7 sig_type=std_logic lab=vdd}
C {vsource.sym} 2070 360 0 0 {name=V4 value=0V savecurrent=false}
C {gnd.sym} 2070 420 0 0 {name=l2 lab=GND}
C {lab_pin.sym} 2070 290 2 0 {name=p8 sig_type=std_logic lab=vss}
C {code_shown.sym} 530 -510 0 0 {name=MODELS only_toplevel=false value=".include /foss/pdks/gf180mcuD/libs.tech/ngspice/design.ngspice
.lib /foss/pdks/gf180mcuD/libs.tech/ngspice/sm141064.ngspice typical
.lib /foss/pdks/gf180mcuD/libs.tech/ngspice/smbb000149.ngspice typical
.lib /foss/pdks/gf180mcuD/libs.tech/ngspice/sm141064.ngspice cap_mim
.lib /foss/pdks/gf180mcuD/libs.tech/ngspice/sm141064.ngspice mimcap_typical"}
C {code_shown.sym} 1870 -190 0 0 {name=NGSPICE only_toplevel=false value="
*.tran 10p 0.3u
.dc V1 0 5 0.001
.save all
.control
run
let slope =deriv(v(out))
meas dc minslope MIN slope
let gain = -minslope
print gain
plot slope
plot v(out)

.endc"

}
